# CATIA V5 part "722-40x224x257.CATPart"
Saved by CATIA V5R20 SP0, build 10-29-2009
Part number: 722-40x224x257
Definition: NONE
Nomenclature: 722-40x224x257
Source: Unknown
Description: 722-40x224x257
Bounding box of the stored display mesh (mm): x -20 to 20, y -20 to 20, z -209 to 48
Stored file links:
  C:\Users\Utente\Desktop\IO LAVORO\3D X SITO CF\X SITO\722\722-40x224x257.CATPart

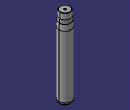
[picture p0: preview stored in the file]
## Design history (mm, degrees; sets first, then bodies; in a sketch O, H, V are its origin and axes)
Body1 "722-40x224x257" (main body)
  Solid1: solid without history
